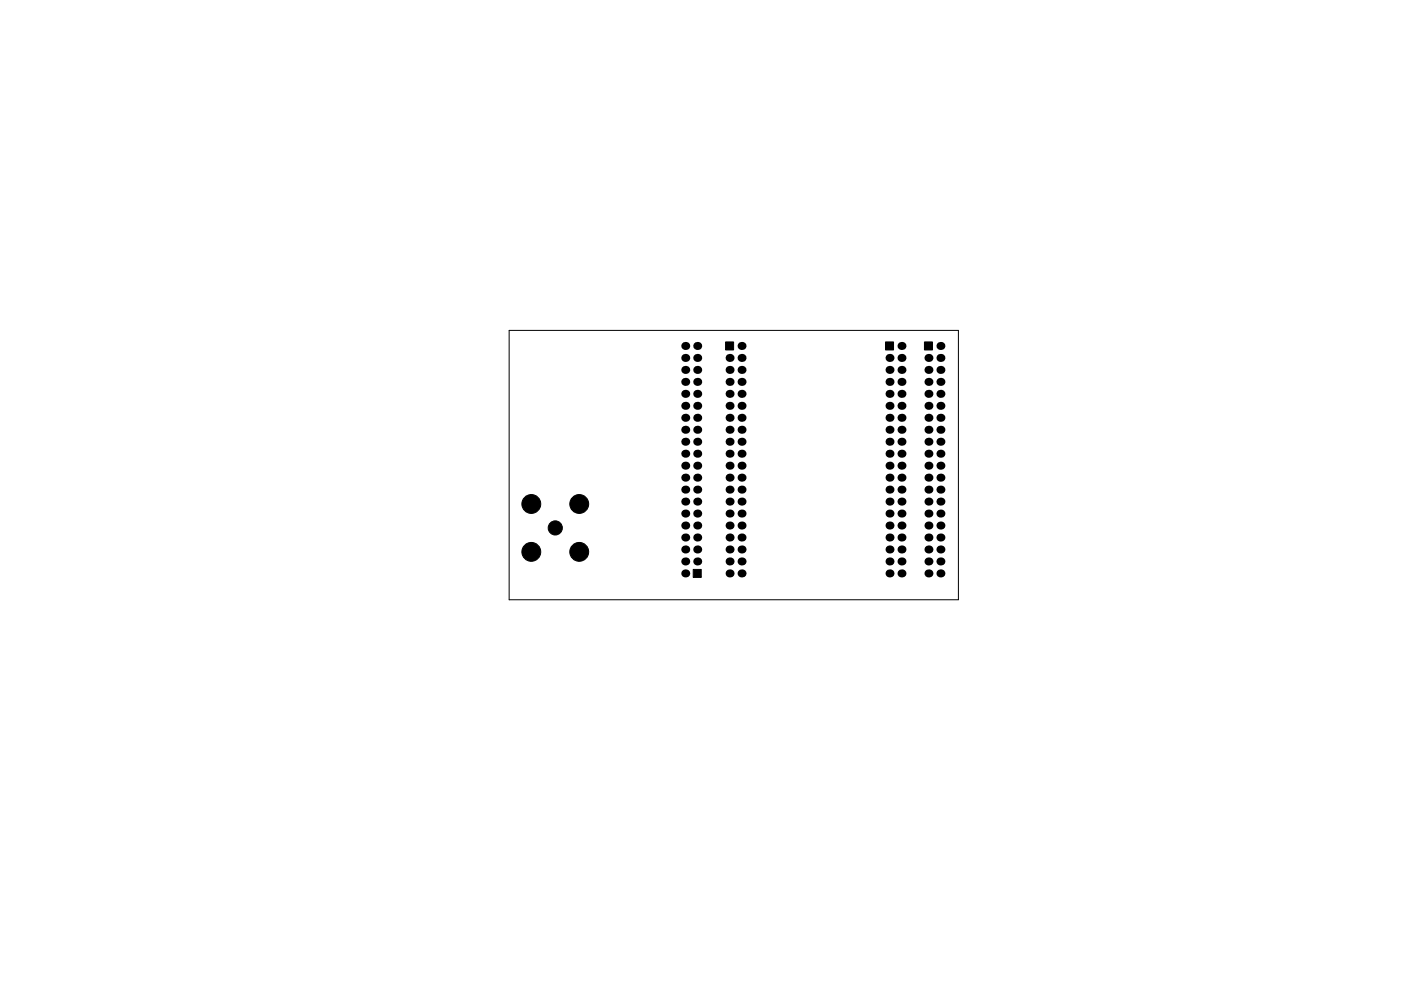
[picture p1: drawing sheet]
<svg xmlns="http://www.w3.org/2000/svg" width="297mm" height="210mm" viewBox="0 0 297 210" stroke-linecap="round" stroke-linejoin="round" font-family="sans-serif">
<path d="M107.9 70.1h95.3v57.1h-95.3z" fill="none" stroke="#000" stroke-width=".21"/>
<g fill="#000" stroke="#000" stroke-width=".21">
<path d="M153.8 72.6h1.7v1.7h-1.7zM187.7 72.6h1.7v1.7h-1.7zM196 72.6h1.7v1.7h-1.7zM147 120.8h1.7v1.7h-1.7z"/>
<circle cx="112.6" cy="106.9" r="2"/>
<circle cx="112.6" cy="117.1" r="2"/>
<circle cx="117.7" cy="112" r="1.5"/>
<circle cx="122.8" cy="106.9" r="2"/>
<circle cx="122.8" cy="117.1" r="2"/>
</g>
<g fill="#000">
<circle cx="145.3" cy="78.5" r=".85"/>
<circle cx="145.3" cy="75.9" r=".85"/>
<circle cx="145.3" cy="73.4" r=".85"/>
<circle cx="147.8" cy="78.5" r=".85"/>
<circle cx="147.8" cy="73.4" r=".85"/>
<circle cx="147.8" cy="75.9" r=".85"/>
<circle cx="154.7" cy="78.5" r=".85"/>
<circle cx="154.7" cy="75.9" r=".85"/>
<circle cx="157.2" cy="78.5" r=".85"/>
<circle cx="157.2" cy="73.4" r=".85"/>
<circle cx="157.2" cy="75.9" r=".85"/>
<circle cx="188.6" cy="78.5" r=".85"/>
<circle cx="188.6" cy="75.9" r=".85"/>
<circle cx="191.1" cy="78.5" r=".85"/>
<circle cx="191.1" cy="73.4" r=".85"/>
<circle cx="191.1" cy="75.9" r=".85"/>
<circle cx="196.8" cy="78.5" r=".85"/>
<circle cx="196.8" cy="75.9" r=".85"/>
<circle cx="199.4" cy="73.4" r=".85"/>
<circle cx="199.4" cy="78.5" r=".85"/>
<circle cx="199.4" cy="75.9" r=".85"/>
<circle cx="145.3" cy="96.3" r=".85"/>
<circle cx="145.3" cy="88.6" r=".85"/>
<circle cx="145.3" cy="83.6" r=".85"/>
<circle cx="145.3" cy="81" r=".85"/>
<circle cx="145.3" cy="93.7" r=".85"/>
<circle cx="145.3" cy="86.1" r=".85"/>
<circle cx="145.3" cy="98.8" r=".85"/>
<circle cx="145.3" cy="91.2" r=".85"/>
<circle cx="147.8" cy="93.7" r=".85"/>
<circle cx="147.8" cy="88.6" r=".85"/>
<circle cx="147.8" cy="86.1" r=".85"/>
<circle cx="147.8" cy="96.3" r=".85"/>
<circle cx="147.8" cy="91.2" r=".85"/>
<circle cx="147.8" cy="81" r=".85"/>
<circle cx="147.8" cy="98.8" r=".85"/>
<circle cx="147.8" cy="83.6" r=".85"/>
<circle cx="154.7" cy="93.7" r=".85"/>
<circle cx="154.7" cy="96.3" r=".85"/>
<circle cx="154.7" cy="81" r=".85"/>
<circle cx="154.7" cy="86.1" r=".85"/>
<circle cx="154.7" cy="83.6" r=".85"/>
<circle cx="154.7" cy="91.2" r=".85"/>
<circle cx="154.7" cy="98.8" r=".85"/>
<circle cx="154.7" cy="88.6" r=".85"/>
<circle cx="157.2" cy="96.3" r=".85"/>
<circle cx="157.2" cy="93.7" r=".85"/>
<circle cx="157.2" cy="86.1" r=".85"/>
<circle cx="157.2" cy="81" r=".85"/>
<circle cx="157.2" cy="83.6" r=".85"/>
<circle cx="157.2" cy="88.6" r=".85"/>
<circle cx="157.2" cy="91.2" r=".85"/>
<circle cx="157.2" cy="98.8" r=".85"/>
<circle cx="188.6" cy="96.3" r=".85"/>
<circle cx="188.6" cy="88.6" r=".85"/>
<circle cx="188.6" cy="86.1" r=".85"/>
<circle cx="188.6" cy="93.7" r=".85"/>
<circle cx="188.6" cy="83.6" r=".85"/>
<circle cx="188.6" cy="91.2" r=".85"/>
<circle cx="188.6" cy="81" r=".85"/>
<circle cx="188.6" cy="98.8" r=".85"/>
<circle cx="191.1" cy="86.1" r=".85"/>
<circle cx="191.1" cy="83.6" r=".85"/>
<circle cx="191.1" cy="88.6" r=".85"/>
<circle cx="191.1" cy="91.2" r=".85"/>
<circle cx="191.1" cy="93.7" r=".85"/>
<circle cx="191.1" cy="96.3" r=".85"/>
<circle cx="191.1" cy="81" r=".85"/>
<circle cx="191.1" cy="98.8" r=".85"/>
<circle cx="196.8" cy="91.2" r=".85"/>
<circle cx="196.8" cy="86.1" r=".85"/>
<circle cx="196.8" cy="88.6" r=".85"/>
<circle cx="196.8" cy="93.7" r=".85"/>
<circle cx="196.8" cy="81" r=".85"/>
<circle cx="196.8" cy="83.6" r=".85"/>
<circle cx="196.8" cy="96.3" r=".85"/>
<circle cx="196.8" cy="98.8" r=".85"/>
<circle cx="199.4" cy="88.6" r=".85"/>
<circle cx="199.4" cy="83.6" r=".85"/>
<circle cx="199.4" cy="86.1" r=".85"/>
<circle cx="199.4" cy="91.2" r=".85"/>
<circle cx="199.4" cy="93.7" r=".85"/>
<circle cx="199.4" cy="96.3" r=".85"/>
<circle cx="199.4" cy="81" r=".85"/>
<circle cx="199.4" cy="98.8" r=".85"/>
<circle cx="145.3" cy="114" r=".85"/>
<circle cx="145.3" cy="119.1" r=".85"/>
<circle cx="145.3" cy="116.6" r=".85"/>
<circle cx="145.3" cy="109" r=".85"/>
<circle cx="145.3" cy="101.3" r=".85"/>
<circle cx="145.3" cy="111.5" r=".85"/>
<circle cx="145.3" cy="103.9" r=".85"/>
<circle cx="145.3" cy="106.4" r=".85"/>
<circle cx="147.8" cy="109" r=".85"/>
<circle cx="147.8" cy="116.6" r=".85"/>
<circle cx="147.8" cy="103.9" r=".85"/>
<circle cx="147.8" cy="119.1" r=".85"/>
<circle cx="147.8" cy="114" r=".85"/>
<circle cx="147.8" cy="111.5" r=".85"/>
<circle cx="147.8" cy="101.3" r=".85"/>
<circle cx="147.8" cy="106.4" r=".85"/>
<circle cx="154.7" cy="103.9" r=".85"/>
<circle cx="154.7" cy="109" r=".85"/>
<circle cx="154.7" cy="116.6" r=".85"/>
<circle cx="154.7" cy="119.1" r=".85"/>
<circle cx="154.7" cy="111.5" r=".85"/>
<circle cx="154.7" cy="114" r=".85"/>
<circle cx="154.7" cy="101.3" r=".85"/>
<circle cx="154.7" cy="106.4" r=".85"/>
<circle cx="157.2" cy="114" r=".85"/>
<circle cx="157.2" cy="119.1" r=".85"/>
<circle cx="157.2" cy="106.4" r=".85"/>
<circle cx="157.2" cy="111.5" r=".85"/>
<circle cx="157.2" cy="116.6" r=".85"/>
<circle cx="157.2" cy="101.3" r=".85"/>
<circle cx="157.2" cy="109" r=".85"/>
<circle cx="157.2" cy="103.9" r=".85"/>
<circle cx="188.6" cy="109" r=".85"/>
<circle cx="188.6" cy="116.6" r=".85"/>
<circle cx="188.6" cy="101.3" r=".85"/>
<circle cx="188.6" cy="103.9" r=".85"/>
<circle cx="188.6" cy="106.4" r=".85"/>
<circle cx="188.6" cy="111.5" r=".85"/>
<circle cx="188.6" cy="119.1" r=".85"/>
<circle cx="188.6" cy="114" r=".85"/>
<circle cx="191.1" cy="111.5" r=".85"/>
<circle cx="191.1" cy="109" r=".85"/>
<circle cx="191.1" cy="116.6" r=".85"/>
<circle cx="191.1" cy="101.3" r=".85"/>
<circle cx="191.1" cy="103.9" r=".85"/>
<circle cx="191.1" cy="106.4" r=".85"/>
<circle cx="191.1" cy="119.1" r=".85"/>
<circle cx="191.1" cy="114" r=".85"/>
<circle cx="196.8" cy="101.3" r=".85"/>
<circle cx="196.8" cy="109" r=".85"/>
<circle cx="196.8" cy="116.6" r=".85"/>
<circle cx="196.8" cy="103.9" r=".85"/>
<circle cx="196.8" cy="106.4" r=".85"/>
<circle cx="196.8" cy="111.5" r=".85"/>
<circle cx="196.8" cy="119.1" r=".85"/>
<circle cx="196.8" cy="114" r=".85"/>
<circle cx="199.4" cy="116.6" r=".85"/>
<circle cx="199.4" cy="101.3" r=".85"/>
<circle cx="199.4" cy="103.9" r=".85"/>
<circle cx="199.4" cy="106.4" r=".85"/>
<circle cx="199.4" cy="109" r=".85"/>
<circle cx="199.4" cy="114" r=".85"/>
<circle cx="199.4" cy="111.5" r=".85"/>
<circle cx="199.4" cy="119.1" r=".85"/>
<circle cx="145.3" cy="121.7" r=".85"/>
<circle cx="154.7" cy="121.7" r=".85"/>
<circle cx="157.2" cy="121.7" r=".85"/>
<circle cx="188.6" cy="121.7" r=".85"/>
<circle cx="191.1" cy="121.7" r=".85"/>
<circle cx="196.8" cy="121.7" r=".85"/>
<circle cx="199.4" cy="121.7" r=".85"/>
</g>
</svg>
